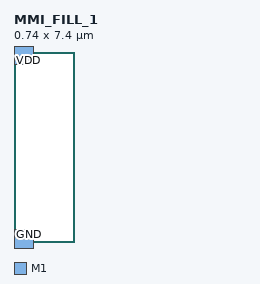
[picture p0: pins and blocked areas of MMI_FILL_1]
MACRO MMI_FILL_1
	CLASS CORE ;
	FOREIGN MMI_FILL_1 0 0 ;
	SIZE 0.74 BY 7.4 ;
	SYMMETRY X Y ;
	SITE CORE1 ;
	PIN GND
		DIRECTION inout ;
		USE GROUND ;
		PORT
			LAYER M1 ;
			RECT 0 -0.5 0.74 0.5 ;
		END
	END GND
	PIN VDD
		DIRECTION inout ;
		USE POWER ;
		PORT
			LAYER M1 ;
			RECT 0 6.9 0.74 7.9 ;
		END
	END VDD
	OBS
	END
END MMI_FILL_1
